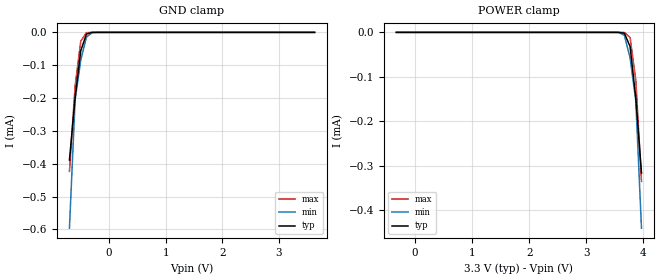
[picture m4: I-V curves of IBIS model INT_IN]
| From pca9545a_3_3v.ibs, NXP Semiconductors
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[Model]   INT_IN
Model_type Input
Vinh=2.1
Vinl=0.9
C_comp   1.73p   1.73p   1.73p
[Temperature Range] 27   85   -40
[Voltage Range]   3.3   2.97   3.63
[POWER Clamp Reference]3.3   2.97   3.63
[GND Clamp Reference]0   0   0
[GND Clamp]
-700mV    -388.8uA   -596.3uA   -423.6uA
-600mV    -199uA     -205.2uA   -162.8uA
-500mV    -55.95uA   -84.45uA   -27.01uA
-400mV    -5.314uA   -14.58uA   -847.7nA
-300mV    -147nA     -737.1nA   -8.808nA
3.63V     11.85pA    25pA       10.9pA
[POWER Clamp]
-330mV    11.85pA    25pA       10.9pA
3.47V     -717.7pA   -5.933nA   -16.46pA
3.57V     -44.33nA   -254nA     -2.09nA
3.67V     -1.999uA   -6.705uA   -228.6nA
3.77V     -31.95uA   -57.22uA   -11.54uA
3.87V     -148.2uA   -153.7uA   -107.4uA
3.97V     -316.4uA   -440.3uA   -335.2uA
